# Generated by FakeRAM 2.0
VERSION 5.7 ;
BUSBITCHARS "[]" ;
PROPERTYDEFINITIONS
  MACRO width INTEGER ;
  MACRO depth INTEGER ;
  MACRO banks INTEGER ;
END PROPERTYDEFINITIONS
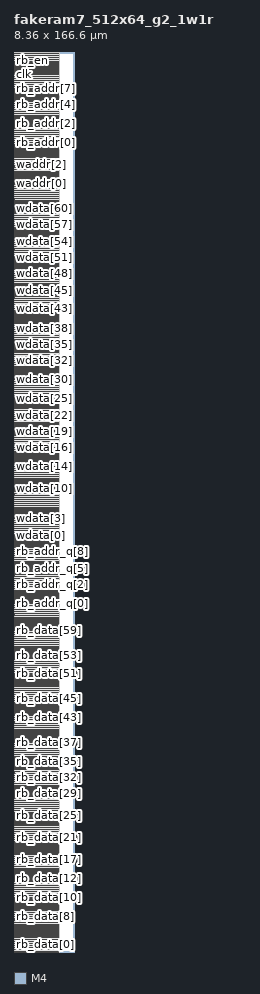
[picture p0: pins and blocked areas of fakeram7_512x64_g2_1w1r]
MACRO fakeram7_512x64_g2_1w1r
  PROPERTY width 64 ;
  PROPERTY depth 512 ;
  PROPERTY banks 1 ;
  FOREIGN fakeram7_512x64_g2_1w1r 0 0 ;
  SYMMETRY X Y R90 ;
  SIZE 8.3600 BY 166.6000 ;
  CLASS BLOCK ;
  PIN wdata[0]
    DIRECTION INPUT ;
    USE SIGNAL ;
    PORT
      LAYER M4 ;
      RECT 0.00000 75.69600 0.02400 75.72000 ;
    END
  END wdata[0]
  PIN wdata[1]
    DIRECTION INPUT ;
    USE SIGNAL ;
    PORT
      LAYER M4 ;
      RECT 0.00000 76.70400 0.02400 76.72800 ;
    END
  END wdata[1]
  PIN wdata[2]
    DIRECTION INPUT ;
    USE SIGNAL ;
    PORT
      LAYER M4 ;
      RECT 0.00000 77.71200 0.02400 77.73600 ;
    END
  END wdata[2]
  PIN wdata[3]
    DIRECTION INPUT ;
    USE SIGNAL ;
    PORT
      LAYER M4 ;
      RECT 0.00000 78.72000 0.02400 78.74400 ;
    END
  END wdata[3]
  PIN wdata[4]
    DIRECTION INPUT ;
    USE SIGNAL ;
    PORT
      LAYER M4 ;
      RECT 0.00000 79.72800 0.02400 79.75200 ;
    END
  END wdata[4]
  PIN wdata[5]
    DIRECTION INPUT ;
    USE SIGNAL ;
    PORT
      LAYER M4 ;
      RECT 0.00000 80.73600 0.02400 80.76000 ;
    END
  END wdata[5]
  PIN wdata[6]
    DIRECTION INPUT ;
    USE SIGNAL ;
    PORT
      LAYER M4 ;
      RECT 0.00000 81.74400 0.02400 81.76800 ;
    END
  END wdata[6]
  PIN wdata[7]
    DIRECTION INPUT ;
    USE SIGNAL ;
    PORT
      LAYER M4 ;
      RECT 0.00000 82.75200 0.02400 82.77600 ;
    END
  END wdata[7]
  PIN wdata[8]
    DIRECTION INPUT ;
    USE SIGNAL ;
    PORT
      LAYER M4 ;
      RECT 0.00000 83.76000 0.02400 83.78400 ;
    END
  END wdata[8]
  PIN wdata[9]
    DIRECTION INPUT ;
    USE SIGNAL ;
    PORT
      LAYER M4 ;
      RECT 0.00000 84.76800 0.02400 84.79200 ;
    END
  END wdata[9]
  PIN wdata[10]
    DIRECTION INPUT ;
    USE SIGNAL ;
    PORT
      LAYER M4 ;
      RECT 0.00000 85.77600 0.02400 85.80000 ;
    END
  END wdata[10]
  PIN wdata[11]
    DIRECTION INPUT ;
    USE SIGNAL ;
    PORT
      LAYER M4 ;
      RECT 0.00000 86.78400 0.02400 86.80800 ;
    END
  END wdata[11]
  PIN wdata[12]
    DIRECTION INPUT ;
    USE SIGNAL ;
    PORT
      LAYER M4 ;
      RECT 0.00000 87.79200 0.02400 87.81600 ;
    END
  END wdata[12]
  PIN wdata[13]
    DIRECTION INPUT ;
    USE SIGNAL ;
    PORT
      LAYER M4 ;
      RECT 0.00000 88.80000 0.02400 88.82400 ;
    END
  END wdata[13]
  PIN wdata[14]
    DIRECTION INPUT ;
    USE SIGNAL ;
    PORT
      LAYER M4 ;
      RECT 0.00000 89.80800 0.02400 89.83200 ;
    END
  END wdata[14]
  PIN wdata[15]
    DIRECTION INPUT ;
    USE SIGNAL ;
    PORT
      LAYER M4 ;
      RECT 0.00000 90.81600 0.02400 90.84000 ;
    END
  END wdata[15]
  PIN wdata[16]
    DIRECTION INPUT ;
    USE SIGNAL ;
    PORT
      LAYER M4 ;
      RECT 0.00000 91.82400 0.02400 91.84800 ;
    END
  END wdata[16]
  PIN wdata[17]
    DIRECTION INPUT ;
    USE SIGNAL ;
    PORT
      LAYER M4 ;
      RECT 0.00000 92.83200 0.02400 92.85600 ;
    END
  END wdata[17]
  PIN wdata[18]
    DIRECTION INPUT ;
    USE SIGNAL ;
    PORT
      LAYER M4 ;
      RECT 0.00000 93.84000 0.02400 93.86400 ;
    END
  END wdata[18]
  PIN wdata[19]
    DIRECTION INPUT ;
    USE SIGNAL ;
    PORT
      LAYER M4 ;
      RECT 0.00000 94.84800 0.02400 94.87200 ;
    END
  END wdata[19]
  PIN wdata[20]
    DIRECTION INPUT ;
    USE SIGNAL ;
    PORT
      LAYER M4 ;
      RECT 0.00000 95.85600 0.02400 95.88000 ;
    END
  END wdata[20]
  PIN wdata[21]
    DIRECTION INPUT ;
    USE SIGNAL ;
    PORT
      LAYER M4 ;
      RECT 0.00000 96.86400 0.02400 96.88800 ;
    END
  END wdata[21]
  PIN wdata[22]
    DIRECTION INPUT ;
    USE SIGNAL ;
    PORT
      LAYER M4 ;
      RECT 0.00000 97.87200 0.02400 97.89600 ;
    END
  END wdata[22]
  PIN wdata[23]
    DIRECTION INPUT ;
    USE SIGNAL ;
    PORT
      LAYER M4 ;
      RECT 0.00000 98.88000 0.02400 98.90400 ;
    END
  END wdata[23]
  PIN wdata[24]
    DIRECTION INPUT ;
    USE SIGNAL ;
    PORT
      LAYER M4 ;
      RECT 0.00000 99.88800 0.02400 99.91200 ;
    END
  END wdata[24]
  PIN wdata[25]
    DIRECTION INPUT ;
    USE SIGNAL ;
    PORT
      LAYER M4 ;
      RECT 0.00000 100.89600 0.02400 100.92000 ;
    END
  END wdata[25]
  PIN wdata[26]
    DIRECTION INPUT ;
    USE SIGNAL ;
    PORT
      LAYER M4 ;
      RECT 0.00000 101.90400 0.02400 101.92800 ;
    END
  END wdata[26]
  PIN wdata[27]
    DIRECTION INPUT ;
    USE SIGNAL ;
    PORT
      LAYER M4 ;
      RECT 0.00000 102.91200 0.02400 102.93600 ;
    END
  END wdata[27]
  PIN wdata[28]
    DIRECTION INPUT ;
    USE SIGNAL ;
    PORT
      LAYER M4 ;
      RECT 0.00000 103.92000 0.02400 103.94400 ;
    END
  END wdata[28]
  PIN wdata[29]
    DIRECTION INPUT ;
    USE SIGNAL ;
    PORT
      LAYER M4 ;
      RECT 0.00000 104.92800 0.02400 104.95200 ;
    END
  END wdata[29]
  PIN wdata[30]
    DIRECTION INPUT ;
    USE SIGNAL ;
    PORT
      LAYER M4 ;
      RECT 0.00000 105.93600 0.02400 105.96000 ;
    END
  END wdata[30]
  PIN wdata[31]
    DIRECTION INPUT ;
    USE SIGNAL ;
    PORT
      LAYER M4 ;
      RECT 0.00000 106.94400 0.02400 106.96800 ;
    END
  END wdata[31]
  PIN wdata[32]
    DIRECTION INPUT ;
    USE SIGNAL ;
    PORT
      LAYER M4 ;
      RECT 0.00000 107.95200 0.02400 107.97600 ;
    END
  END wdata[32]
  PIN wdata[33]
    DIRECTION INPUT ;
    USE SIGNAL ;
    PORT
      LAYER M4 ;
      RECT 0.00000 108.96000 0.02400 108.98400 ;
    END
  END wdata[33]
  PIN wdata[34]
    DIRECTION INPUT ;
    USE SIGNAL ;
    PORT
      LAYER M4 ;
      RECT 0.00000 109.96800 0.02400 109.99200 ;
    END
  END wdata[34]
  PIN wdata[35]
    DIRECTION INPUT ;
    USE SIGNAL ;
    PORT
      LAYER M4 ;
      RECT 0.00000 110.97600 0.02400 111.00000 ;
    END
  END wdata[35]
  PIN wdata[36]
    DIRECTION INPUT ;
    USE SIGNAL ;
    PORT
      LAYER M4 ;
      RECT 0.00000 111.98400 0.02400 112.00800 ;
    END
  END wdata[36]
  PIN wdata[37]
    DIRECTION INPUT ;
    USE SIGNAL ;
    PORT
      LAYER M4 ;
      RECT 0.00000 112.99200 0.02400 113.01600 ;
    END
  END wdata[37]
  PIN wdata[38]
    DIRECTION INPUT ;
    USE SIGNAL ;
    PORT
      LAYER M4 ;
      RECT 0.00000 114.00000 0.02400 114.02400 ;
    END
  END wdata[38]
  PIN wdata[39]
    DIRECTION INPUT ;
    USE SIGNAL ;
    PORT
      LAYER M4 ;
      RECT 0.00000 115.00800 0.02400 115.03200 ;
    END
  END wdata[39]
  PIN wdata[40]
    DIRECTION INPUT ;
    USE SIGNAL ;
    PORT
      LAYER M4 ;
      RECT 0.00000 116.01600 0.02400 116.04000 ;
    END
  END wdata[40]
  PIN wdata[41]
    DIRECTION INPUT ;
    USE SIGNAL ;
    PORT
      LAYER M4 ;
      RECT 0.00000 117.02400 0.02400 117.04800 ;
    END
  END wdata[41]
  PIN wdata[42]
    DIRECTION INPUT ;
    USE SIGNAL ;
    PORT
      LAYER M4 ;
      RECT 0.00000 118.03200 0.02400 118.05600 ;
    END
  END wdata[42]
  PIN wdata[43]
    DIRECTION INPUT ;
    USE SIGNAL ;
    PORT
      LAYER M4 ;
      RECT 0.00000 119.04000 0.02400 119.06400 ;
    END
  END wdata[43]
  PIN wdata[44]
    DIRECTION INPUT ;
    USE SIGNAL ;
    PORT
      LAYER M4 ;
      RECT 0.00000 120.04800 0.02400 120.07200 ;
    END
  END wdata[44]
  PIN wdata[45]
    DIRECTION INPUT ;
    USE SIGNAL ;
    PORT
      LAYER M4 ;
      RECT 0.00000 121.05600 0.02400 121.08000 ;
    END
  END wdata[45]
  PIN wdata[46]
    DIRECTION INPUT ;
    USE SIGNAL ;
    PORT
      LAYER M4 ;
      RECT 0.00000 122.06400 0.02400 122.08800 ;
    END
  END wdata[46]
  PIN wdata[47]
    DIRECTION INPUT ;
    USE SIGNAL ;
    PORT
      LAYER M4 ;
      RECT 0.00000 123.07200 0.02400 123.09600 ;
    END
  END wdata[47]
  PIN wdata[48]
    DIRECTION INPUT ;
    USE SIGNAL ;
    PORT
      LAYER M4 ;
      RECT 0.00000 124.08000 0.02400 124.10400 ;
    END
  END wdata[48]
  PIN wdata[49]
    DIRECTION INPUT ;
    USE SIGNAL ;
    PORT
      LAYER M4 ;
      RECT 0.00000 125.08800 0.02400 125.11200 ;
    END
  END wdata[49]
  PIN wdata[50]
    DIRECTION INPUT ;
    USE SIGNAL ;
    PORT
      LAYER M4 ;
      RECT 0.00000 126.09600 0.02400 126.12000 ;
    END
  END wdata[50]
  PIN wdata[51]
    DIRECTION INPUT ;
    USE SIGNAL ;
    PORT
      LAYER M4 ;
      RECT 0.00000 127.10400 0.02400 127.12800 ;
    END
  END wdata[51]
  PIN wdata[52]
    DIRECTION INPUT ;
    USE SIGNAL ;
    PORT
      LAYER M4 ;
      RECT 0.00000 128.11200 0.02400 128.13600 ;
    END
  END wdata[52]
  PIN wdata[53]
    DIRECTION INPUT ;
    USE SIGNAL ;
    PORT
      LAYER M4 ;
      RECT 0.00000 129.12000 0.02400 129.14400 ;
    END
  END wdata[53]
  PIN wdata[54]
    DIRECTION INPUT ;
    USE SIGNAL ;
    PORT
      LAYER M4 ;
      RECT 0.00000 130.12800 0.02400 130.15200 ;
    END
  END wdata[54]
  PIN wdata[55]
    DIRECTION INPUT ;
    USE SIGNAL ;
    PORT
      LAYER M4 ;
      RECT 0.00000 131.13600 0.02400 131.16000 ;
    END
  END wdata[55]
  PIN wdata[56]
    DIRECTION INPUT ;
    USE SIGNAL ;
    PORT
      LAYER M4 ;
      RECT 0.00000 132.14400 0.02400 132.16800 ;
    END
  END wdata[56]
  PIN wdata[57]
    DIRECTION INPUT ;
    USE SIGNAL ;
    PORT
      LAYER M4 ;
      RECT 0.00000 133.15200 0.02400 133.17600 ;
    END
  END wdata[57]
  PIN wdata[58]
    DIRECTION INPUT ;
    USE SIGNAL ;
    PORT
      LAYER M4 ;
      RECT 0.00000 134.16000 0.02400 134.18400 ;
    END
  END wdata[58]
  PIN wdata[59]
    DIRECTION INPUT ;
    USE SIGNAL ;
    PORT
      LAYER M4 ;
      RECT 0.00000 135.16800 0.02400 135.19200 ;
    END
  END wdata[59]
  PIN wdata[60]
    DIRECTION INPUT ;
    USE SIGNAL ;
    PORT
      LAYER M4 ;
      RECT 0.00000 136.17600 0.02400 136.20000 ;
    END
  END wdata[60]
  PIN wdata[61]
    DIRECTION INPUT ;
    USE SIGNAL ;
    PORT
      LAYER M4 ;
      RECT 0.00000 137.18400 0.02400 137.20800 ;
    END
  END wdata[61]
  PIN wdata[62]
    DIRECTION INPUT ;
    USE SIGNAL ;
    PORT
      LAYER M4 ;
      RECT 0.00000 138.19200 0.02400 138.21600 ;
    END
  END wdata[62]
  PIN wdata[63]
    DIRECTION INPUT ;
    USE SIGNAL ;
    PORT
      LAYER M4 ;
      RECT 0.00000 139.20000 0.02400 139.22400 ;
    END
  END wdata[63]
  PIN waddr[0]
    DIRECTION INPUT ;
    USE SIGNAL ;
    PORT
      LAYER M4 ;
      RECT 0.00000 142.27200 0.02400 142.29600 ;
    END
  END waddr[0]
  PIN waddr[1]
    DIRECTION INPUT ;
    USE SIGNAL ;
    PORT
      LAYER M4 ;
      RECT 0.00000 143.28000 0.02400 143.30400 ;
    END
  END waddr[1]
  PIN waddr[2]
    DIRECTION INPUT ;
    USE SIGNAL ;
    PORT
      LAYER M4 ;
      RECT 0.00000 144.28800 0.02400 144.31200 ;
    END
  END waddr[2]
  PIN waddr[3]
    DIRECTION INPUT ;
    USE SIGNAL ;
    PORT
      LAYER M4 ;
      RECT 0.00000 145.29600 0.02400 145.32000 ;
    END
  END waddr[3]
  PIN waddr[4]
    DIRECTION INPUT ;
    USE SIGNAL ;
    PORT
      LAYER M4 ;
      RECT 0.00000 146.30400 0.02400 146.32800 ;
    END
  END waddr[4]
  PIN waddr[5]
    DIRECTION INPUT ;
    USE SIGNAL ;
    PORT
      LAYER M4 ;
      RECT 0.00000 147.31200 0.02400 147.33600 ;
    END
  END waddr[5]
  PIN waddr[6]
    DIRECTION INPUT ;
    USE SIGNAL ;
    PORT
      LAYER M4 ;
      RECT 0.00000 148.32000 0.02400 148.34400 ;
    END
  END waddr[6]
  PIN waddr[7]
    DIRECTION INPUT ;
    USE SIGNAL ;
    PORT
      LAYER M4 ;
      RECT 0.00000 149.32800 0.02400 149.35200 ;
    END
  END waddr[7]
  PIN waddr[8]
    DIRECTION INPUT ;
    USE SIGNAL ;
    PORT
      LAYER M4 ;
      RECT 0.00000 150.33600 0.02400 150.36000 ;
    END
  END waddr[8]
  PIN rb_data[0]
    DIRECTION OUTPUT ;
    USE SIGNAL ;
    PORT
      LAYER M4 ;
      RECT 0.00000 0.04800 0.02400 0.07200 ;
    END
  END rb_data[0]
  PIN rb_data[1]
    DIRECTION OUTPUT ;
    USE SIGNAL ;
    PORT
      LAYER M4 ;
      RECT 0.00000 1.05600 0.02400 1.08000 ;
    END
  END rb_data[1]
  PIN rb_data[2]
    DIRECTION OUTPUT ;
    USE SIGNAL ;
    PORT
      LAYER M4 ;
      RECT 0.00000 2.06400 0.02400 2.08800 ;
    END
  END rb_data[2]
  PIN rb_data[3]
    DIRECTION OUTPUT ;
    USE SIGNAL ;
    PORT
      LAYER M4 ;
      RECT 0.00000 3.07200 0.02400 3.09600 ;
    END
  END rb_data[3]
  PIN rb_data[4]
    DIRECTION OUTPUT ;
    USE SIGNAL ;
    PORT
      LAYER M4 ;
      RECT 0.00000 4.08000 0.02400 4.10400 ;
    END
  END rb_data[4]
  PIN rb_data[5]
    DIRECTION OUTPUT ;
    USE SIGNAL ;
    PORT
      LAYER M4 ;
      RECT 0.00000 5.08800 0.02400 5.11200 ;
    END
  END rb_data[5]
  PIN rb_data[6]
    DIRECTION OUTPUT ;
    USE SIGNAL ;
    PORT
      LAYER M4 ;
      RECT 0.00000 6.09600 0.02400 6.12000 ;
    END
  END rb_data[6]
  PIN rb_data[7]
    DIRECTION OUTPUT ;
    USE SIGNAL ;
    PORT
      LAYER M4 ;
      RECT 0.00000 7.10400 0.02400 7.12800 ;
    END
  END rb_data[7]
  PIN rb_data[8]
    DIRECTION OUTPUT ;
    USE SIGNAL ;
    PORT
      LAYER M4 ;
      RECT 0.00000 8.11200 0.02400 8.13600 ;
    END
  END rb_data[8]
  PIN rb_data[9]
    DIRECTION OUTPUT ;
    USE SIGNAL ;
    PORT
      LAYER M4 ;
      RECT 0.00000 9.12000 0.02400 9.14400 ;
    END
  END rb_data[9]
  PIN rb_data[10]
    DIRECTION OUTPUT ;
    USE SIGNAL ;
    PORT
      LAYER M4 ;
      RECT 0.00000 10.12800 0.02400 10.15200 ;
    END
  END rb_data[10]
  PIN rb_data[11]
    DIRECTION OUTPUT ;
    USE SIGNAL ;
    PORT
      LAYER M4 ;
      RECT 0.00000 11.13600 0.02400 11.16000 ;
    END
  END rb_data[11]
  PIN rb_data[12]
    DIRECTION OUTPUT ;
    USE SIGNAL ;
    PORT
      LAYER M4 ;
      RECT 0.00000 12.14400 0.02400 12.16800 ;
    END
  END rb_data[12]
  PIN rb_data[13]
    DIRECTION OUTPUT ;
    USE SIGNAL ;
    PORT
      LAYER M4 ;
      RECT 0.00000 13.15200 0.02400 13.17600 ;
    END
  END rb_data[13]
  PIN rb_data[14]
    DIRECTION OUTPUT ;
    USE SIGNAL ;
    PORT
      LAYER M4 ;
      RECT 0.00000 14.16000 0.02400 14.18400 ;
    END
  END rb_data[14]
  PIN rb_data[15]
    DIRECTION OUTPUT ;
    USE SIGNAL ;
    PORT
      LAYER M4 ;
      RECT 0.00000 15.16800 0.02400 15.19200 ;
    END
  END rb_data[15]
  PIN rb_data[16]
    DIRECTION OUTPUT ;
    USE SIGNAL ;
    PORT
      LAYER M4 ;
      RECT 0.00000 16.17600 0.02400 16.20000 ;
    END
  END rb_data[16]
  PIN rb_data[17]
    DIRECTION OUTPUT ;
    USE SIGNAL ;
    PORT
      LAYER M4 ;
      RECT 0.00000 17.18400 0.02400 17.20800 ;
    END
  END rb_data[17]
  PIN rb_data[18]
    DIRECTION OUTPUT ;
    USE SIGNAL ;
    PORT
      LAYER M4 ;
      RECT 0.00000 18.19200 0.02400 18.21600 ;
    END
  END rb_data[18]
  PIN rb_data[19]
    DIRECTION OUTPUT ;
    USE SIGNAL ;
    PORT
      LAYER M4 ;
      RECT 0.00000 19.20000 0.02400 19.22400 ;
    END
  END rb_data[19]
  PIN rb_data[20]
    DIRECTION OUTPUT ;
    USE SIGNAL ;
    PORT
      LAYER M4 ;
      RECT 0.00000 20.20800 0.02400 20.23200 ;
    END
  END rb_data[20]
  PIN rb_data[21]
    DIRECTION OUTPUT ;
    USE SIGNAL ;
    PORT
      LAYER M4 ;
      RECT 0.00000 21.21600 0.02400 21.24000 ;
    END
  END rb_data[21]
  PIN rb_data[22]
    DIRECTION OUTPUT ;
    USE SIGNAL ;
    PORT
      LAYER M4 ;
      RECT 0.00000 22.22400 0.02400 22.24800 ;
    END
  END rb_data[22]
  PIN rb_data[23]
    DIRECTION OUTPUT ;
    USE SIGNAL ;
    PORT
      LAYER M4 ;
      RECT 0.00000 23.23200 0.02400 23.25600 ;
    END
  END rb_data[23]
  PIN rb_data[24]
    DIRECTION OUTPUT ;
    USE SIGNAL ;
    PORT
      LAYER M4 ;
      RECT 0.00000 24.24000 0.02400 24.26400 ;
    END
  END rb_data[24]
  PIN rb_data[25]
    DIRECTION OUTPUT ;
    USE SIGNAL ;
    PORT
      LAYER M4 ;
      RECT 0.00000 25.24800 0.02400 25.27200 ;
    END
  END rb_data[25]
  PIN rb_data[26]
    DIRECTION OUTPUT ;
    USE SIGNAL ;
    PORT
      LAYER M4 ;
      RECT 0.00000 26.25600 0.02400 26.28000 ;
    END
  END rb_data[26]
  PIN rb_data[27]
    DIRECTION OUTPUT ;
    USE SIGNAL ;
    PORT
      LAYER M4 ;
      RECT 0.00000 27.26400 0.02400 27.28800 ;
    END
  END rb_data[27]
  PIN rb_data[28]
    DIRECTION OUTPUT ;
    USE SIGNAL ;
    PORT
      LAYER M4 ;
      RECT 0.00000 28.27200 0.02400 28.29600 ;
    END
  END rb_data[28]
  PIN rb_data[29]
    DIRECTION OUTPUT ;
    USE SIGNAL ;
    PORT
      LAYER M4 ;
      RECT 0.00000 29.28000 0.02400 29.30400 ;
    END
  END rb_data[29]
  PIN rb_data[30]
    DIRECTION OUTPUT ;
    USE SIGNAL ;
    PORT
      LAYER M4 ;
      RECT 0.00000 30.28800 0.02400 30.31200 ;
    END
  END rb_data[30]
  PIN rb_data[31]
    DIRECTION OUTPUT ;
    USE SIGNAL ;
    PORT
      LAYER M4 ;
      RECT 0.00000 31.29600 0.02400 31.32000 ;
    END
  END rb_data[31]
  PIN rb_data[32]
    DIRECTION OUTPUT ;
    USE SIGNAL ;
    PORT
      LAYER M4 ;
      RECT 0.00000 32.30400 0.02400 32.32800 ;
    END
  END rb_data[32]
  PIN rb_data[33]
    DIRECTION OUTPUT ;
    USE SIGNAL ;
    PORT
      LAYER M4 ;
      RECT 0.00000 33.31200 0.02400 33.33600 ;
    END
  END rb_data[33]
  PIN rb_data[34]
    DIRECTION OUTPUT ;
    USE SIGNAL ;
    PORT
      LAYER M4 ;
      RECT 0.00000 34.32000 0.02400 34.34400 ;
    END
  END rb_data[34]
  PIN rb_data[35]
    DIRECTION OUTPUT ;
    USE SIGNAL ;
    PORT
      LAYER M4 ;
      RECT 0.00000 35.32800 0.02400 35.35200 ;
    END
  END rb_data[35]
  PIN rb_data[36]
    DIRECTION OUTPUT ;
    USE SIGNAL ;
    PORT
      LAYER M4 ;
      RECT 0.00000 36.33600 0.02400 36.36000 ;
    END
  END rb_data[36]
  PIN rb_data[37]
    DIRECTION OUTPUT ;
    USE SIGNAL ;
    PORT
      LAYER M4 ;
      RECT 0.00000 37.34400 0.02400 37.36800 ;
    END
  END rb_data[37]
  PIN rb_data[38]
    DIRECTION OUTPUT ;
    USE SIGNAL ;
    PORT
      LAYER M4 ;
      RECT 0.00000 38.35200 0.02400 38.37600 ;
    END
  END rb_data[38]
  PIN rb_data[39]
    DIRECTION OUTPUT ;
    USE SIGNAL ;
    PORT
      LAYER M4 ;
      RECT 0.00000 39.36000 0.02400 39.38400 ;
    END
  END rb_data[39]
  PIN rb_data[40]
    DIRECTION OUTPUT ;
    USE SIGNAL ;
    PORT
      LAYER M4 ;
      RECT 0.00000 40.36800 0.02400 40.39200 ;
    END
  END rb_data[40]
  PIN rb_data[41]
    DIRECTION OUTPUT ;
    USE SIGNAL ;
    PORT
      LAYER M4 ;
      RECT 0.00000 41.37600 0.02400 41.40000 ;
    END
  END rb_data[41]
  PIN rb_data[42]
    DIRECTION OUTPUT ;
    USE SIGNAL ;
    PORT
      LAYER M4 ;
      RECT 0.00000 42.38400 0.02400 42.40800 ;
    END
  END rb_data[42]
  PIN rb_data[43]
    DIRECTION OUTPUT ;
    USE SIGNAL ;
    PORT
      LAYER M4 ;
      RECT 0.00000 43.39200 0.02400 43.41600 ;
    END
  END rb_data[43]
  PIN rb_data[44]
    DIRECTION OUTPUT ;
    USE SIGNAL ;
    PORT
      LAYER M4 ;
      RECT 0.00000 44.40000 0.02400 44.42400 ;
    END
  END rb_data[44]
  PIN rb_data[45]
    DIRECTION OUTPUT ;
    USE SIGNAL ;
    PORT
      LAYER M4 ;
      RECT 0.00000 45.40800 0.02400 45.43200 ;
    END
  END rb_data[45]
  PIN rb_data[46]
    DIRECTION OUTPUT ;
    USE SIGNAL ;
    PORT
      LAYER M4 ;
      RECT 0.00000 46.41600 0.02400 46.44000 ;
    END
  END rb_data[46]
  PIN rb_data[47]
    DIRECTION OUTPUT ;
    USE SIGNAL ;
    PORT
      LAYER M4 ;
      RECT 0.00000 47.42400 0.02400 47.44800 ;
    END
  END rb_data[47]
  PIN rb_data[48]
    DIRECTION OUTPUT ;
    USE SIGNAL ;
    PORT
      LAYER M4 ;
      RECT 0.00000 48.43200 0.02400 48.45600 ;
    END
  END rb_data[48]
  PIN rb_data[49]
    DIRECTION OUTPUT ;
    USE SIGNAL ;
    PORT
      LAYER M4 ;
      RECT 0.00000 49.44000 0.02400 49.46400 ;
    END
  END rb_data[49]
  PIN rb_data[50]
    DIRECTION OUTPUT ;
    USE SIGNAL ;
    PORT
      LAYER M4 ;
      RECT 0.00000 50.44800 0.02400 50.47200 ;
    END
  END rb_data[50]
  PIN rb_data[51]
    DIRECTION OUTPUT ;
    USE SIGNAL ;
    PORT
      LAYER M4 ;
      RECT 0.00000 51.45600 0.02400 51.48000 ;
    END
  END rb_data[51]
  PIN rb_data[52]
    DIRECTION OUTPUT ;
    USE SIGNAL ;
    PORT
      LAYER M4 ;
      RECT 0.00000 52.46400 0.02400 52.48800 ;
    END
  END rb_data[52]
  PIN rb_data[53]
    DIRECTION OUTPUT ;
    USE SIGNAL ;
    PORT
      LAYER M4 ;
      RECT 0.00000 53.47200 0.02400 53.49600 ;
    END
  END rb_data[53]
  PIN rb_data[54]
    DIRECTION OUTPUT ;
    USE SIGNAL ;
    PORT
      LAYER M4 ;
      RECT 0.00000 54.48000 0.02400 54.50400 ;
    END
  END rb_data[54]
  PIN rb_data[55]
    DIRECTION OUTPUT ;
    USE SIGNAL ;
    PORT
      LAYER M4 ;
      RECT 0.00000 55.48800 0.02400 55.51200 ;
    END
  END rb_data[55]
  PIN rb_data[56]
    DIRECTION OUTPUT ;
    USE SIGNAL ;
    PORT
      LAYER M4 ;
      RECT 0.00000 56.49600 0.02400 56.52000 ;
    END
  END rb_data[56]
  PIN rb_data[57]
    DIRECTION OUTPUT ;
    USE SIGNAL ;
    PORT
      LAYER M4 ;
      RECT 0.00000 57.50400 0.02400 57.52800 ;
    END
  END rb_data[57]
  PIN rb_data[58]
    DIRECTION OUTPUT ;
    USE SIGNAL ;
    PORT
      LAYER M4 ;
      RECT 0.00000 58.51200 0.02400 58.53600 ;
    END
  END rb_data[58]
  PIN rb_data[59]
    DIRECTION OUTPUT ;
    USE SIGNAL ;
    PORT
      LAYER M4 ;
      RECT 0.00000 59.52000 0.02400 59.54400 ;
    END
  END rb_data[59]
  PIN rb_data[60]
    DIRECTION OUTPUT ;
    USE SIGNAL ;
    PORT
      LAYER M4 ;
      RECT 0.00000 60.52800 0.02400 60.55200 ;
    END
  END rb_data[60]
  PIN rb_data[61]
    DIRECTION OUTPUT ;
    USE SIGNAL ;
    PORT
      LAYER M4 ;
      RECT 0.00000 61.53600 0.02400 61.56000 ;
    END
  END rb_data[61]
  PIN rb_data[62]
    DIRECTION OUTPUT ;
    USE SIGNAL ;
    PORT
      LAYER M4 ;
      RECT 0.00000 62.54400 0.02400 62.56800 ;
    END
  END rb_data[62]
  PIN rb_data[63]
    DIRECTION OUTPUT ;
    USE SIGNAL ;
    PORT
      LAYER M4 ;
      RECT 0.00000 63.55200 0.02400 63.57600 ;
    END
  END rb_data[63]
  PIN rb_addr[0]
    DIRECTION INPUT ;
    USE SIGNAL ;
    PORT
      LAYER M4 ;
      RECT 0.00000 151.34400 0.02400 151.36800 ;
    END
  END rb_addr[0]
  PIN rb_addr[1]
    DIRECTION INPUT ;
    USE SIGNAL ;
    PORT
      LAYER M4 ;
      RECT 0.00000 152.35200 0.02400 152.37600 ;
    END
  END rb_addr[1]
  PIN rb_addr[2]
    DIRECTION INPUT ;
    USE SIGNAL ;
    PORT
      LAYER M4 ;
      RECT 0.00000 153.36000 0.02400 153.38400 ;
    END
  END rb_addr[2]
  PIN rb_addr[3]
    DIRECTION INPUT ;
    USE SIGNAL ;
    PORT
      LAYER M4 ;
      RECT 0.00000 154.36800 0.02400 154.39200 ;
    END
  END rb_addr[3]
  PIN rb_addr[4]
    DIRECTION INPUT ;
    USE SIGNAL ;
    PORT
      LAYER M4 ;
      RECT 0.00000 155.37600 0.02400 155.40000 ;
    END
  END rb_addr[4]
  PIN rb_addr[5]
    DIRECTION INPUT ;
    USE SIGNAL ;
    PORT
      LAYER M4 ;
      RECT 0.00000 156.38400 0.02400 156.40800 ;
    END
  END rb_addr[5]
  PIN rb_addr[6]
    DIRECTION INPUT ;
    USE SIGNAL ;
    PORT
      LAYER M4 ;
      RECT 0.00000 157.39200 0.02400 157.41600 ;
    END
  END rb_addr[6]
  PIN rb_addr[7]
    DIRECTION INPUT ;
    USE SIGNAL ;
    PORT
      LAYER M4 ;
      RECT 0.00000 158.40000 0.02400 158.42400 ;
    END
  END rb_addr[7]
  PIN rb_addr[8]
    DIRECTION INPUT ;
    USE SIGNAL ;
    PORT
      LAYER M4 ;
      RECT 0.00000 159.40800 0.02400 159.43200 ;
    END
  END rb_addr[8]
  PIN we[0]
    DIRECTION INPUT ;
    USE SIGNAL ;
    PORT
      LAYER M4 ;
      RECT 0.00000 163.48800 0.02400 163.51200 ;
    END
  END we[0]
  PIN we[1]
    DIRECTION INPUT ;
    USE SIGNAL ;
    PORT
      LAYER M4 ;
      RECT 0.00000 164.49600 0.02400 164.52000 ;
    END
  END we[1]
  PIN clk
    DIRECTION INPUT ;
    USE SIGNAL ;
    PORT
      LAYER M4 ;
      RECT 0.00000 162.48000 0.02400 162.50400 ;
    END
  END clk
  PIN rb_en
    DIRECTION INPUT ;
    USE SIGNAL ;
    PORT
      LAYER M4 ;
      RECT 0.00000 165.50400 0.02400 165.52800 ;
    END
  END rb_en
  PIN rb_addr_q[0]
    DIRECTION OUTPUT ;
    USE SIGNAL ;
    PORT
      LAYER M4 ;
      RECT 0.00000 64.56000 0.02400 64.58400 ;
    END
  END rb_addr_q[0]
  PIN rb_addr_q[1]
    DIRECTION OUTPUT ;
    USE SIGNAL ;
    PORT
      LAYER M4 ;
      RECT 0.00000 65.56800 0.02400 65.59200 ;
    END
  END rb_addr_q[1]
  PIN rb_addr_q[2]
    DIRECTION OUTPUT ;
    USE SIGNAL ;
    PORT
      LAYER M4 ;
      RECT 0.00000 66.57600 0.02400 66.60000 ;
    END
  END rb_addr_q[2]
  PIN rb_addr_q[3]
    DIRECTION OUTPUT ;
    USE SIGNAL ;
    PORT
      LAYER M4 ;
      RECT 0.00000 67.58400 0.02400 67.60800 ;
    END
  END rb_addr_q[3]
  PIN rb_addr_q[4]
    DIRECTION OUTPUT ;
    USE SIGNAL ;
    PORT
      LAYER M4 ;
      RECT 0.00000 68.59200 0.02400 68.61600 ;
    END
  END rb_addr_q[4]
  PIN rb_addr_q[5]
    DIRECTION OUTPUT ;
    USE SIGNAL ;
    PORT
      LAYER M4 ;
      RECT 0.00000 69.60000 0.02400 69.62400 ;
    END
  END rb_addr_q[5]
  PIN rb_addr_q[6]
    DIRECTION OUTPUT ;
    USE SIGNAL ;
    PORT
      LAYER M4 ;
      RECT 0.00000 70.60800 0.02400 70.63200 ;
    END
  END rb_addr_q[6]
  PIN rb_addr_q[7]
    DIRECTION OUTPUT ;
    USE SIGNAL ;
    PORT
      LAYER M4 ;
      RECT 0.00000 71.61600 0.02400 71.64000 ;
    END
  END rb_addr_q[7]
  PIN rb_addr_q[8]
    DIRECTION OUTPUT ;
    USE SIGNAL ;
    PORT
      LAYER M4 ;
      RECT 0.00000 72.62400 0.02400 72.64800 ;
    END
  END rb_addr_q[8]
  PIN VDD
    DIRECTION INOUT ;
    USE POWER ;
    PORT
      LAYER M4 ;
      RECT 0.04800 0.38400 8.31200 0.48000 ;
      RECT 0.04800 1.15200 8.31200 1.24800 ;
      RECT 0.04800 1.92000 8.31200 2.01600 ;
      RECT 0.04800 2.68800 8.31200 2.78400 ;
      RECT 0.04800 3.45600 8.31200 3.55200 ;
      RECT 0.04800 4.22400 8.31200 4.32000 ;
      RECT 0.04800 4.99200 8.31200 5.08800 ;
      RECT 0.04800 5.76000 8.31200 5.85600 ;
      RECT 0.04800 6.52800 8.31200 6.62400 ;
      RECT 0.04800 7.29600 8.31200 7.39200 ;
      RECT 0.04800 8.06400 8.31200 8.16000 ;
      RECT 0.04800 8.83200 8.31200 8.92800 ;
      RECT 0.04800 9.60000 8.31200 9.69600 ;
      RECT 0.04800 10.36800 8.31200 10.46400 ;
      RECT 0.04800 11.13600 8.31200 11.23200 ;
      RECT 0.04800 11.90400 8.31200 12.00000 ;
      RECT 0.04800 12.67200 8.31200 12.76800 ;
      RECT 0.04800 13.44000 8.31200 13.53600 ;
      RECT 0.04800 14.20800 8.31200 14.30400 ;
      RECT 0.04800 14.97600 8.31200 15.07200 ;
      RECT 0.04800 15.74400 8.31200 15.84000 ;
      RECT 0.04800 16.51200 8.31200 16.60800 ;
      RECT 0.04800 17.28000 8.31200 17.37600 ;
      RECT 0.04800 18.04800 8.31200 18.14400 ;
      RECT 0.04800 18.81600 8.31200 18.91200 ;
      RECT 0.04800 19.58400 8.31200 19.68000 ;
      RECT 0.04800 20.35200 8.31200 20.44800 ;
      RECT 0.04800 21.12000 8.31200 21.21600 ;
      RECT 0.04800 21.88800 8.31200 21.98400 ;
      RECT 0.04800 22.65600 8.31200 22.75200 ;
      RECT 0.04800 23.42400 8.31200 23.52000 ;
      RECT 0.04800 24.19200 8.31200 24.28800 ;
      RECT 0.04800 24.96000 8.31200 25.05600 ;
      RECT 0.04800 25.72800 8.31200 25.82400 ;
      RECT 0.04800 26.49600 8.31200 26.59200 ;
      RECT 0.04800 27.26400 8.31200 27.36000 ;
      RECT 0.04800 28.03200 8.31200 28.12800 ;
      RECT 0.04800 28.80000 8.31200 28.89600 ;
      RECT 0.04800 29.56800 8.31200 29.66400 ;
      RECT 0.04800 30.33600 8.31200 30.43200 ;
      RECT 0.04800 31.10400 8.31200 31.20000 ;
      RECT 0.04800 31.87200 8.31200 31.96800 ;
      RECT 0.04800 32.64000 8.31200 32.73600 ;
      RECT 0.04800 33.40800 8.31200 33.50400 ;
      RECT 0.04800 34.17600 8.31200 34.27200 ;
      RECT 0.04800 34.94400 8.31200 35.04000 ;
      RECT 0.04800 35.71200 8.31200 35.80800 ;
      RECT 0.04800 36.48000 8.31200 36.57600 ;
      RECT 0.04800 37.24800 8.31200 37.34400 ;
      RECT 0.04800 38.01600 8.31200 38.11200 ;
      RECT 0.04800 38.78400 8.31200 38.88000 ;
      RECT 0.04800 39.55200 8.31200 39.64800 ;
      RECT 0.04800 40.32000 8.31200 40.41600 ;
      RECT 0.04800 41.08800 8.31200 41.18400 ;
      RECT 0.04800 41.85600 8.31200 41.95200 ;
      RECT 0.04800 42.62400 8.31200 42.72000 ;
      RECT 0.04800 43.39200 8.31200 43.48800 ;
      RECT 0.04800 44.16000 8.31200 44.25600 ;
      RECT 0.04800 44.92800 8.31200 45.02400 ;
      RECT 0.04800 45.69600 8.31200 45.79200 ;
      RECT 0.04800 46.46400 8.31200 46.56000 ;
      RECT 0.04800 47.23200 8.31200 47.32800 ;
      RECT 0.04800 48.00000 8.31200 48.09600 ;
      RECT 0.04800 48.76800 8.31200 48.86400 ;
      RECT 0.04800 49.53600 8.31200 49.63200 ;
      RECT 0.04800 50.30400 8.31200 50.40000 ;
      RECT 0.04800 51.07200 8.31200 51.16800 ;
      RECT 0.04800 51.84000 8.31200 51.93600 ;
      RECT 0.04800 52.60800 8.31200 52.70400 ;
      RECT 0.04800 53.37600 8.31200 53.47200 ;
      RECT 0.04800 54.14400 8.31200 54.24000 ;
      RECT 0.04800 54.91200 8.31200 55.00800 ;
      RECT 0.04800 55.68000 8.31200 55.77600 ;
      RECT 0.04800 56.44800 8.31200 56.54400 ;
      RECT 0.04800 57.21600 8.31200 57.31200 ;
      RECT 0.04800 57.98400 8.31200 58.08000 ;
      RECT 0.04800 58.75200 8.31200 58.84800 ;
      RECT 0.04800 59.52000 8.31200 59.61600 ;
      RECT 0.04800 60.28800 8.31200 60.38400 ;
      RECT 0.04800 61.05600 8.31200 61.15200 ;
      RECT 0.04800 61.82400 8.31200 61.92000 ;
      RECT 0.04800 62.59200 8.31200 62.68800 ;
      RECT 0.04800 63.36000 8.31200 63.45600 ;
      RECT 0.04800 64.12800 8.31200 64.22400 ;
      RECT 0.04800 64.89600 8.31200 64.99200 ;
      RECT 0.04800 65.66400 8.31200 65.76000 ;
      RECT 0.04800 66.43200 8.31200 66.52800 ;
      RECT 0.04800 67.20000 8.31200 67.29600 ;
      RECT 0.04800 67.96800 8.31200 68.06400 ;
      RECT 0.04800 68.73600 8.31200 68.83200 ;
      RECT 0.04800 69.50400 8.31200 69.60000 ;
      RECT 0.04800 70.27200 8.31200 70.36800 ;
      RECT 0.04800 71.04000 8.31200 71.13600 ;
      RECT 0.04800 71.80800 8.31200 71.90400 ;
      RECT 0.04800 72.57600 8.31200 72.67200 ;
      RECT 0.04800 73.34400 8.31200 73.44000 ;
      RECT 0.04800 74.11200 8.31200 74.20800 ;
      RECT 0.04800 74.88000 8.31200 74.97600 ;
      RECT 0.04800 75.64800 8.31200 75.74400 ;
      RECT 0.04800 76.41600 8.31200 76.51200 ;
      RECT 0.04800 77.18400 8.31200 77.28000 ;
      RECT 0.04800 77.95200 8.31200 78.04800 ;
      RECT 0.04800 78.72000 8.31200 78.81600 ;
      RECT 0.04800 79.48800 8.31200 79.58400 ;
      RECT 0.04800 80.25600 8.31200 80.35200 ;
      RECT 0.04800 81.02400 8.31200 81.12000 ;
      RECT 0.04800 81.79200 8.31200 81.88800 ;
      RECT 0.04800 82.56000 8.31200 82.65600 ;
      RECT 0.04800 83.32800 8.31200 83.42400 ;
      RECT 0.04800 84.09600 8.31200 84.19200 ;
      RECT 0.04800 84.86400 8.31200 84.96000 ;
      RECT 0.04800 85.63200 8.31200 85.72800 ;
      RECT 0.04800 86.40000 8.31200 86.49600 ;
      RECT 0.04800 87.16800 8.31200 87.26400 ;
      RECT 0.04800 87.93600 8.31200 88.03200 ;
      RECT 0.04800 88.70400 8.31200 88.80000 ;
      RECT 0.04800 89.47200 8.31200 89.56800 ;
      RECT 0.04800 90.24000 8.31200 90.33600 ;
      RECT 0.04800 91.00800 8.31200 91.10400 ;
      RECT 0.04800 91.77600 8.31200 91.87200 ;
      RECT 0.04800 92.54400 8.31200 92.64000 ;
      RECT 0.04800 93.31200 8.31200 93.40800 ;
      RECT 0.04800 94.08000 8.31200 94.17600 ;
      RECT 0.04800 94.84800 8.31200 94.94400 ;
      RECT 0.04800 95.61600 8.31200 95.71200 ;
      RECT 0.04800 96.38400 8.31200 96.48000 ;
      RECT 0.04800 97.15200 8.31200 97.24800 ;
      RECT 0.04800 97.92000 8.31200 98.01600 ;
      RECT 0.04800 98.68800 8.31200 98.78400 ;
      RECT 0.04800 99.45600 8.31200 99.55200 ;
      RECT 0.04800 100.22400 8.31200 100.32000 ;
      RECT 0.04800 100.99200 8.31200 101.08800 ;
      RECT 0.04800 101.76000 8.31200 101.85600 ;
      RECT 0.04800 102.52800 8.31200 102.62400 ;
      RECT 0.04800 103.29600 8.31200 103.39200 ;
      RECT 0.04800 104.06400 8.31200 104.16000 ;
      RECT 0.04800 104.83200 8.31200 104.92800 ;
      RECT 0.04800 105.60000 8.31200 105.69600 ;
      RECT 0.04800 106.36800 8.31200 106.46400 ;
      RECT 0.04800 107.13600 8.31200 107.23200 ;
      RECT 0.04800 107.90400 8.31200 108.00000 ;
      RECT 0.04800 108.67200 8.31200 108.76800 ;
      RECT 0.04800 109.44000 8.31200 109.53600 ;
      RECT 0.04800 110.20800 8.31200 110.30400 ;
      RECT 0.04800 110.97600 8.31200 111.07200 ;
      RECT 0.04800 111.74400 8.31200 111.84000 ;
      RECT 0.04800 112.51200 8.31200 112.60800 ;
      RECT 0.04800 113.28000 8.31200 113.37600 ;
      RECT 0.04800 114.04800 8.31200 114.14400 ;
      RECT 0.04800 114.81600 8.31200 114.91200 ;
      RECT 0.04800 115.58400 8.31200 115.68000 ;
      RECT 0.04800 116.35200 8.31200 116.44800 ;
      RECT 0.04800 117.12000 8.31200 117.21600 ;
      RECT 0.04800 117.88800 8.31200 117.98400 ;
      RECT 0.04800 118.65600 8.31200 118.75200 ;
      RECT 0.04800 119.42400 8.31200 119.52000 ;
      RECT 0.04800 120.19200 8.31200 120.28800 ;
      RECT 0.04800 120.96000 8.31200 121.05600 ;
      RECT 0.04800 121.72800 8.31200 121.82400 ;
      RECT 0.04800 122.49600 8.31200 122.59200 ;
      RECT 0.04800 123.26400 8.31200 123.36000 ;
      RECT 0.04800 124.03200 8.31200 124.12800 ;
      RECT 0.04800 124.80000 8.31200 124.89600 ;
      RECT 0.04800 125.56800 8.31200 125.66400 ;
      RECT 0.04800 126.33600 8.31200 126.43200 ;
      RECT 0.04800 127.10400 8.31200 127.20000 ;
      RECT 0.04800 127.87200 8.31200 127.96800 ;
      RECT 0.04800 128.64000 8.31200 128.73600 ;
      RECT 0.04800 129.40800 8.31200 129.50400 ;
      RECT 0.04800 130.17600 8.31200 130.27200 ;
      RECT 0.04800 130.94400 8.31200 131.04000 ;
      RECT 0.04800 131.71200 8.31200 131.80800 ;
      RECT 0.04800 132.48000 8.31200 132.57600 ;
      RECT 0.04800 133.24800 8.31200 133.34400 ;
      RECT 0.04800 134.01600 8.31200 134.11200 ;
      RECT 0.04800 134.78400 8.31200 134.88000 ;
      RECT 0.04800 135.55200 8.31200 135.64800 ;
      RECT 0.04800 136.32000 8.31200 136.41600 ;
      RECT 0.04800 137.08800 8.31200 137.18400 ;
      RECT 0.04800 137.85600 8.31200 137.95200 ;
      RECT 0.04800 138.62400 8.31200 138.72000 ;
      RECT 0.04800 139.39200 8.31200 139.48800 ;
      RECT 0.04800 140.16000 8.31200 140.25600 ;
      RECT 0.04800 140.92800 8.31200 141.02400 ;
      RECT 0.04800 141.69600 8.31200 141.79200 ;
      RECT 0.04800 142.46400 8.31200 142.56000 ;
      RECT 0.04800 143.23200 8.31200 143.32800 ;
      RECT 0.04800 144.00000 8.31200 144.09600 ;
      RECT 0.04800 144.76800 8.31200 144.86400 ;
      RECT 0.04800 145.53600 8.31200 145.63200 ;
      RECT 0.04800 146.30400 8.31200 146.40000 ;
      RECT 0.04800 147.07200 8.31200 147.16800 ;
      RECT 0.04800 147.84000 8.31200 147.93600 ;
      RECT 0.04800 148.60800 8.31200 148.70400 ;
      RECT 0.04800 149.37600 8.31200 149.47200 ;
      RECT 0.04800 150.14400 8.31200 150.24000 ;
      RECT 0.04800 150.91200 8.31200 151.00800 ;
      RECT 0.04800 151.68000 8.31200 151.77600 ;
      RECT 0.04800 152.44800 8.31200 152.54400 ;
      RECT 0.04800 153.21600 8.31200 153.31200 ;
      RECT 0.04800 153.98400 8.31200 154.08000 ;
      RECT 0.04800 154.75200 8.31200 154.84800 ;
      RECT 0.04800 155.52000 8.31200 155.61600 ;
      RECT 0.04800 156.28800 8.31200 156.38400 ;
      RECT 0.04800 157.05600 8.31200 157.15200 ;
      RECT 0.04800 157.82400 8.31200 157.92000 ;
      RECT 0.04800 158.59200 8.31200 158.68800 ;
      RECT 0.04800 159.36000 8.31200 159.45600 ;
      RECT 0.04800 160.12800 8.31200 160.22400 ;
      RECT 0.04800 160.89600 8.31200 160.99200 ;
      RECT 0.04800 161.66400 8.31200 161.76000 ;
      RECT 0.04800 162.43200 8.31200 162.52800 ;
      RECT 0.04800 163.20000 8.31200 163.29600 ;
      RECT 0.04800 163.96800 8.31200 164.06400 ;
      RECT 0.04800 164.73600 8.31200 164.83200 ;
      RECT 0.04800 165.50400 8.31200 165.60000 ;
      RECT 0.04800 166.27200 8.31200 166.36800 ;
    END
  END VDD
  PIN VSS
    DIRECTION INOUT ;
    USE GROUND ;
    PORT
      LAYER M4 ;
      RECT 0.04800 0.00000 8.31200 0.09600 ;
      RECT 0.04800 0.76800 8.31200 0.86400 ;
      RECT 0.04800 1.53600 8.31200 1.63200 ;
      RECT 0.04800 2.30400 8.31200 2.40000 ;
      RECT 0.04800 3.07200 8.31200 3.16800 ;
      RECT 0.04800 3.84000 8.31200 3.93600 ;
      RECT 0.04800 4.60800 8.31200 4.70400 ;
      RECT 0.04800 5.37600 8.31200 5.47200 ;
      RECT 0.04800 6.14400 8.31200 6.24000 ;
      RECT 0.04800 6.91200 8.31200 7.00800 ;
      RECT 0.04800 7.68000 8.31200 7.77600 ;
      RECT 0.04800 8.44800 8.31200 8.54400 ;
      RECT 0.04800 9.21600 8.31200 9.31200 ;
      RECT 0.04800 9.98400 8.31200 10.08000 ;
      RECT 0.04800 10.75200 8.31200 10.84800 ;
      RECT 0.04800 11.52000 8.31200 11.61600 ;
      RECT 0.04800 12.28800 8.31200 12.38400 ;
      RECT 0.04800 13.05600 8.31200 13.15200 ;
      RECT 0.04800 13.82400 8.31200 13.92000 ;
      RECT 0.04800 14.59200 8.31200 14.68800 ;
      RECT 0.04800 15.36000 8.31200 15.45600 ;
      RECT 0.04800 16.12800 8.31200 16.22400 ;
      RECT 0.04800 16.89600 8.31200 16.99200 ;
      RECT 0.04800 17.66400 8.31200 17.76000 ;
      RECT 0.04800 18.43200 8.31200 18.52800 ;
      RECT 0.04800 19.20000 8.31200 19.29600 ;
      RECT 0.04800 19.96800 8.31200 20.06400 ;
      RECT 0.04800 20.73600 8.31200 20.83200 ;
      RECT 0.04800 21.50400 8.31200 21.60000 ;
      RECT 0.04800 22.27200 8.31200 22.36800 ;
      RECT 0.04800 23.04000 8.31200 23.13600 ;
      RECT 0.04800 23.80800 8.31200 23.90400 ;
      RECT 0.04800 24.57600 8.31200 24.67200 ;
      RECT 0.04800 25.34400 8.31200 25.44000 ;
      RECT 0.04800 26.11200 8.31200 26.20800 ;
      RECT 0.04800 26.88000 8.31200 26.97600 ;
      RECT 0.04800 27.64800 8.31200 27.74400 ;
      RECT 0.04800 28.41600 8.31200 28.51200 ;
      RECT 0.04800 29.18400 8.31200 29.28000 ;
      RECT 0.04800 29.95200 8.31200 30.04800 ;
      RECT 0.04800 30.72000 8.31200 30.81600 ;
      RECT 0.04800 31.48800 8.31200 31.58400 ;
      RECT 0.04800 32.25600 8.31200 32.35200 ;
      RECT 0.04800 33.02400 8.31200 33.12000 ;
      RECT 0.04800 33.79200 8.31200 33.88800 ;
      RECT 0.04800 34.56000 8.31200 34.65600 ;
      RECT 0.04800 35.32800 8.31200 35.42400 ;
      RECT 0.04800 36.09600 8.31200 36.19200 ;
      RECT 0.04800 36.86400 8.31200 36.96000 ;
      RECT 0.04800 37.63200 8.31200 37.72800 ;
      RECT 0.04800 38.40000 8.31200 38.49600 ;
      RECT 0.04800 39.16800 8.31200 39.26400 ;
      RECT 0.04800 39.93600 8.31200 40.03200 ;
      RECT 0.04800 40.70400 8.31200 40.80000 ;
      RECT 0.04800 41.47200 8.31200 41.56800 ;
      RECT 0.04800 42.24000 8.31200 42.33600 ;
      RECT 0.04800 43.00800 8.31200 43.10400 ;
      RECT 0.04800 43.77600 8.31200 43.87200 ;
      RECT 0.04800 44.54400 8.31200 44.64000 ;
      RECT 0.04800 45.31200 8.31200 45.40800 ;
      RECT 0.04800 46.08000 8.31200 46.17600 ;
      RECT 0.04800 46.84800 8.31200 46.94400 ;
      RECT 0.04800 47.61600 8.31200 47.71200 ;
      RECT 0.04800 48.38400 8.31200 48.48000 ;
      RECT 0.04800 49.15200 8.31200 49.24800 ;
      RECT 0.04800 49.92000 8.31200 50.01600 ;
      RECT 0.04800 50.68800 8.31200 50.78400 ;
      RECT 0.04800 51.45600 8.31200 51.55200 ;
      RECT 0.04800 52.22400 8.31200 52.32000 ;
      RECT 0.04800 52.99200 8.31200 53.08800 ;
      RECT 0.04800 53.76000 8.31200 53.85600 ;
      RECT 0.04800 54.52800 8.31200 54.62400 ;
      RECT 0.04800 55.29600 8.31200 55.39200 ;
      RECT 0.04800 56.06400 8.31200 56.16000 ;
      RECT 0.04800 56.83200 8.31200 56.92800 ;
      RECT 0.04800 57.60000 8.31200 57.69600 ;
      RECT 0.04800 58.36800 8.31200 58.46400 ;
      RECT 0.04800 59.13600 8.31200 59.23200 ;
      RECT 0.04800 59.90400 8.31200 60.00000 ;
      RECT 0.04800 60.67200 8.31200 60.76800 ;
      RECT 0.04800 61.44000 8.31200 61.53600 ;
      RECT 0.04800 62.20800 8.31200 62.30400 ;
      RECT 0.04800 62.97600 8.31200 63.07200 ;
      RECT 0.04800 63.74400 8.31200 63.84000 ;
      RECT 0.04800 64.51200 8.31200 64.60800 ;
      RECT 0.04800 65.28000 8.31200 65.37600 ;
      RECT 0.04800 66.04800 8.31200 66.14400 ;
      RECT 0.04800 66.81600 8.31200 66.91200 ;
      RECT 0.04800 67.58400 8.31200 67.68000 ;
      RECT 0.04800 68.35200 8.31200 68.44800 ;
      RECT 0.04800 69.12000 8.31200 69.21600 ;
      RECT 0.04800 69.88800 8.31200 69.98400 ;
      RECT 0.04800 70.65600 8.31200 70.75200 ;
      RECT 0.04800 71.42400 8.31200 71.52000 ;
      RECT 0.04800 72.19200 8.31200 72.28800 ;
      RECT 0.04800 72.96000 8.31200 73.05600 ;
      RECT 0.04800 73.72800 8.31200 73.82400 ;
      RECT 0.04800 74.49600 8.31200 74.59200 ;
      RECT 0.04800 75.26400 8.31200 75.36000 ;
      RECT 0.04800 76.03200 8.31200 76.12800 ;
      RECT 0.04800 76.80000 8.31200 76.89600 ;
      RECT 0.04800 77.56800 8.31200 77.66400 ;
      RECT 0.04800 78.33600 8.31200 78.43200 ;
      RECT 0.04800 79.10400 8.31200 79.20000 ;
      RECT 0.04800 79.87200 8.31200 79.96800 ;
      RECT 0.04800 80.64000 8.31200 80.73600 ;
      RECT 0.04800 81.40800 8.31200 81.50400 ;
      RECT 0.04800 82.17600 8.31200 82.27200 ;
      RECT 0.04800 82.94400 8.31200 83.04000 ;
      RECT 0.04800 83.71200 8.31200 83.80800 ;
      RECT 0.04800 84.48000 8.31200 84.57600 ;
      RECT 0.04800 85.24800 8.31200 85.34400 ;
      RECT 0.04800 86.01600 8.31200 86.11200 ;
      RECT 0.04800 86.78400 8.31200 86.88000 ;
      RECT 0.04800 87.55200 8.31200 87.64800 ;
      RECT 0.04800 88.32000 8.31200 88.41600 ;
      RECT 0.04800 89.08800 8.31200 89.18400 ;
      RECT 0.04800 89.85600 8.31200 89.95200 ;
      RECT 0.04800 90.62400 8.31200 90.72000 ;
      RECT 0.04800 91.39200 8.31200 91.48800 ;
      RECT 0.04800 92.16000 8.31200 92.25600 ;
      RECT 0.04800 92.92800 8.31200 93.02400 ;
      RECT 0.04800 93.69600 8.31200 93.79200 ;
      RECT 0.04800 94.46400 8.31200 94.56000 ;
      RECT 0.04800 95.23200 8.31200 95.32800 ;
      RECT 0.04800 96.00000 8.31200 96.09600 ;
      RECT 0.04800 96.76800 8.31200 96.86400 ;
      RECT 0.04800 97.53600 8.31200 97.63200 ;
      RECT 0.04800 98.30400 8.31200 98.40000 ;
      RECT 0.04800 99.07200 8.31200 99.16800 ;
      RECT 0.04800 99.84000 8.31200 99.93600 ;
      RECT 0.04800 100.60800 8.31200 100.70400 ;
      RECT 0.04800 101.37600 8.31200 101.47200 ;
      RECT 0.04800 102.14400 8.31200 102.24000 ;
      RECT 0.04800 102.91200 8.31200 103.00800 ;
      RECT 0.04800 103.68000 8.31200 103.77600 ;
      RECT 0.04800 104.44800 8.31200 104.54400 ;
      RECT 0.04800 105.21600 8.31200 105.31200 ;
      RECT 0.04800 105.98400 8.31200 106.08000 ;
      RECT 0.04800 106.75200 8.31200 106.84800 ;
      RECT 0.04800 107.52000 8.31200 107.61600 ;
      RECT 0.04800 108.28800 8.31200 108.38400 ;
      RECT 0.04800 109.05600 8.31200 109.15200 ;
      RECT 0.04800 109.82400 8.31200 109.92000 ;
      RECT 0.04800 110.59200 8.31200 110.68800 ;
      RECT 0.04800 111.36000 8.31200 111.45600 ;
      RECT 0.04800 112.12800 8.31200 112.22400 ;
      RECT 0.04800 112.89600 8.31200 112.99200 ;
      RECT 0.04800 113.66400 8.31200 113.76000 ;
      RECT 0.04800 114.43200 8.31200 114.52800 ;
      RECT 0.04800 115.20000 8.31200 115.29600 ;
      RECT 0.04800 115.96800 8.31200 116.06400 ;
      RECT 0.04800 116.73600 8.31200 116.83200 ;
      RECT 0.04800 117.50400 8.31200 117.60000 ;
      RECT 0.04800 118.27200 8.31200 118.36800 ;
      RECT 0.04800 119.04000 8.31200 119.13600 ;
      RECT 0.04800 119.80800 8.31200 119.90400 ;
      RECT 0.04800 120.57600 8.31200 120.67200 ;
      RECT 0.04800 121.34400 8.31200 121.44000 ;
      RECT 0.04800 122.11200 8.31200 122.20800 ;
      RECT 0.04800 122.88000 8.31200 122.97600 ;
      RECT 0.04800 123.64800 8.31200 123.74400 ;
      RECT 0.04800 124.41600 8.31200 124.51200 ;
      RECT 0.04800 125.18400 8.31200 125.28000 ;
      RECT 0.04800 125.95200 8.31200 126.04800 ;
      RECT 0.04800 126.72000 8.31200 126.81600 ;
      RECT 0.04800 127.48800 8.31200 127.58400 ;
      RECT 0.04800 128.25600 8.31200 128.35200 ;
      RECT 0.04800 129.02400 8.31200 129.12000 ;
      RECT 0.04800 129.79200 8.31200 129.88800 ;
      RECT 0.04800 130.56000 8.31200 130.65600 ;
      RECT 0.04800 131.32800 8.31200 131.42400 ;
      RECT 0.04800 132.09600 8.31200 132.19200 ;
      RECT 0.04800 132.86400 8.31200 132.96000 ;
      RECT 0.04800 133.63200 8.31200 133.72800 ;
      RECT 0.04800 134.40000 8.31200 134.49600 ;
      RECT 0.04800 135.16800 8.31200 135.26400 ;
      RECT 0.04800 135.93600 8.31200 136.03200 ;
      RECT 0.04800 136.70400 8.31200 136.80000 ;
      RECT 0.04800 137.47200 8.31200 137.56800 ;
      RECT 0.04800 138.24000 8.31200 138.33600 ;
      RECT 0.04800 139.00800 8.31200 139.10400 ;
      RECT 0.04800 139.77600 8.31200 139.87200 ;
      RECT 0.04800 140.54400 8.31200 140.64000 ;
      RECT 0.04800 141.31200 8.31200 141.40800 ;
      RECT 0.04800 142.08000 8.31200 142.17600 ;
      RECT 0.04800 142.84800 8.31200 142.94400 ;
      RECT 0.04800 143.61600 8.31200 143.71200 ;
      RECT 0.04800 144.38400 8.31200 144.48000 ;
      RECT 0.04800 145.15200 8.31200 145.24800 ;
      RECT 0.04800 145.92000 8.31200 146.01600 ;
      RECT 0.04800 146.68800 8.31200 146.78400 ;
      RECT 0.04800 147.45600 8.31200 147.55200 ;
      RECT 0.04800 148.22400 8.31200 148.32000 ;
      RECT 0.04800 148.99200 8.31200 149.08800 ;
      RECT 0.04800 149.76000 8.31200 149.85600 ;
      RECT 0.04800 150.52800 8.31200 150.62400 ;
      RECT 0.04800 151.29600 8.31200 151.39200 ;
      RECT 0.04800 152.06400 8.31200 152.16000 ;
      RECT 0.04800 152.83200 8.31200 152.92800 ;
      RECT 0.04800 153.60000 8.31200 153.69600 ;
      RECT 0.04800 154.36800 8.31200 154.46400 ;
      RECT 0.04800 155.13600 8.31200 155.23200 ;
      RECT 0.04800 155.90400 8.31200 156.00000 ;
      RECT 0.04800 156.67200 8.31200 156.76800 ;
      RECT 0.04800 157.44000 8.31200 157.53600 ;
      RECT 0.04800 158.20800 8.31200 158.30400 ;
      RECT 0.04800 158.97600 8.31200 159.07200 ;
      RECT 0.04800 159.74400 8.31200 159.84000 ;
      RECT 0.04800 160.51200 8.31200 160.60800 ;
      RECT 0.04800 161.28000 8.31200 161.37600 ;
      RECT 0.04800 162.04800 8.31200 162.14400 ;
      RECT 0.04800 162.81600 8.31200 162.91200 ;
      RECT 0.04800 163.58400 8.31200 163.68000 ;
      RECT 0.04800 164.35200 8.31200 164.44800 ;
      RECT 0.04800 165.12000 8.31200 165.21600 ;
      RECT 0.04800 165.88800 8.31200 165.98400 ;
    END
  END VSS
  OBS
    LAYER M1 ;
    RECT 0 0 8.36000 166.60000 ;
    LAYER M2 ;
    RECT 0 0 8.36000 166.60000 ;
    LAYER M3 ;
    RECT 0 0 8.36000 166.60000 ;
    LAYER M4 ;
    RECT 0 0 8.36000 166.60000 ;
  END
END fakeram7_512x64_g2_1w1r

END LIBRARY
